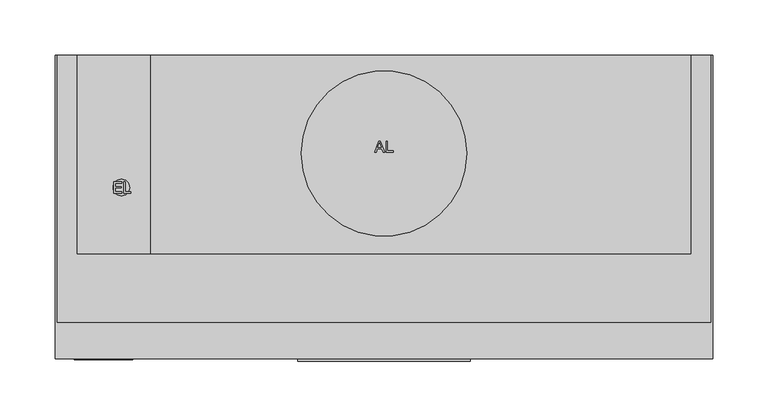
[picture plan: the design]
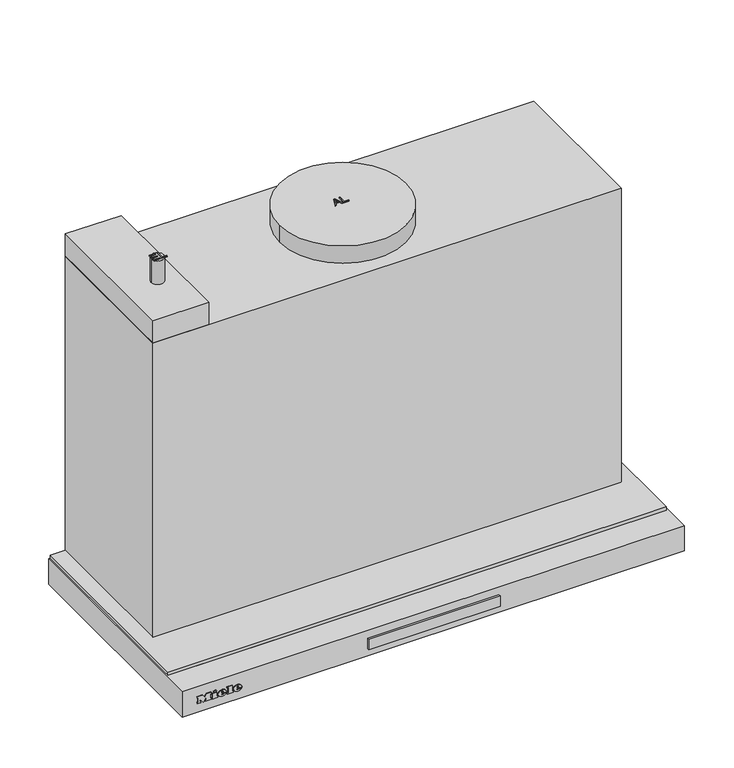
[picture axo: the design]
"""IFC4 building model written with IfcOpenShell, lengths in millimetres: proxy geometry."""

import ifcopenshell
import ifcopenshell.guid

model = None  # the IFC model being written
_history = None  # IfcOwnerHistory: only IFC2X3 demands one
_inside = {}  # id of a spatial element -> (the spatial element, [elements in it])
_under = {}  # id of a project, library or spatial element -> (it, [spatial elements below it])
_declared = {}  # id of a project -> (the project, [libraries it declares])
_typed = {}  # id of a type object -> (the type object, [elements of that type])
_made_of = {}  # id of a material, layer set ... -> (it, [elements and type objects made of it])


def new_model(schema):
    """Start an empty IFC model of exactly this schema.

    Asked for "IFC4X3", IfcOpenShell would pick the latest addendum, in which some entities
    have other attributes; the version numbers below select the first issue.
    IFC2X3 requires an IfcOwnerHistory on every rooted entity: one is made here for all.
    """
    global model, _history
    if schema == "IFC4X3":
        model = ifcopenshell.file(schema_version=(4, 3, 0, 0))
    else:
        model = ifcopenshell.file(schema=schema)
    _inside.clear()
    _under.clear()
    _declared.clear()
    _typed.clear()
    _made_of.clear()
    _history = None
    if model.schema == "IFC2X3":
        org = make("IfcOrganization", Name="unknown")
        user = make(
            "IfcPersonAndOrganization",
            ThePerson=make("IfcPerson", FamilyName="unknown"),
            TheOrganization=org,
        )
        app = make(
            "IfcApplication",
            ApplicationDeveloper=org,
            Version="unknown",
            ApplicationFullName="unknown",
            ApplicationIdentifier="unknown",
        )
        _history = make(
            "IfcOwnerHistory",
            OwningUser=user,
            OwningApplication=app,
            ChangeAction="ADDED",
            CreationDate=0,
        )
    return model


def make(cls, **values):
    """One entity of the class cls with the attributes given. An attribute that is None is left unset."""
    return model.create_entity(
        cls, **{name: value for name, value in values.items() if value is not None}
    )


def rooted(cls, **values):
    """An entity with a GlobalId (a new one), such as an element, a storey or a relation."""
    return make(cls, GlobalId=ifcopenshell.guid.new(), OwnerHistory=_history, **values)


def si_unit(unit_type, name, prefix=None):
    """IfcSIUnit, for example si_unit("LENGTHUNIT", "METRE", prefix="MILLI")."""
    return make("IfcSIUnit", UnitType=unit_type, Prefix=prefix, Name=name)


def assignment(units):
    """IfcUnitAssignment: the units of a project."""
    return None if units is None else make("IfcUnitAssignment", Units=units)


def point(xyz):
    """IfcCartesianPoint."""
    return None if xyz is None else make("IfcCartesianPoint", Coordinates=xyz)


def direction(xyz):
    """IfcDirection."""
    return None if xyz is None else make("IfcDirection", DirectionRatios=xyz)


def frame(location, z_axis=None, x_axis=None):
    """IfcAxis2Placement3D, a coordinate frame: its origin and axes. An axis left out is left unset."""
    return make(
        "IfcAxis2Placement3D",
        Location=point(location),
        Axis=direction(z_axis),
        RefDirection=direction(x_axis),
    )


def frame_2d(location, x_axis=None):
    """IfcAxis2Placement2D, a coordinate frame in the plane: its origin and x axis."""
    return make(
        "IfcAxis2Placement2D", Location=point(location), RefDirection=direction(x_axis)
    )


def origin():
    """The frame at (0, 0, 0) with its axes left unset."""
    return frame((0.0, 0.0, 0.0))


def origin_with_axes():
    """The frame at (0, 0, 0) with the z axis (0, 0, 1) and the x axis (1, 0, 0) written out."""
    return frame((0.0, 0.0, 0.0), z_axis=(0.0, 0.0, 1.0), x_axis=(1.0, 0.0, 0.0))


def place(relative_to, where):
    """IfcLocalPlacement: puts the frame where relative to a parent placement (None: the world)."""
    return make(
        "IfcLocalPlacement", PlacementRelTo=relative_to, RelativePlacement=where
    )


def context(
    kind, dimensions, precision=None, world=None, true_north=None, identifier=None
):
    """IfcGeometricRepresentationContext, for example the 3D "Model" context."""
    return make(
        "IfcGeometricRepresentationContext",
        ContextIdentifier=identifier,
        ContextType=kind,
        CoordinateSpaceDimension=dimensions,
        Precision=precision,
        WorldCoordinateSystem=world,
        TrueNorth=true_north,
    )


def project(units=None, contexts=None):
    """IfcProject with its units and contexts."""
    return rooted(
        "IfcProject",
        Name="project",
        RepresentationContexts=contexts,
        UnitsInContext=assignment(units),
    )


def spatial(cls, under=None, at=None, **own):
    """A site, building, storey or space (cls), placed at a placement, below another one or the project."""
    s = rooted(cls, ObjectPlacement=at, **own)
    if under is not None:
        _under.setdefault(under.id(), (under, []))[1].append(s)
    return s


def polyline(points):
    """IfcPolyline through the points."""
    return make("IfcPolyline", Points=[point(p) for p in points])


def circle_curve(where, radius):
    """IfcCircle in the frame where."""
    return make("IfcCircle", Position=where, Radius=radius)


def ellipse_curve(where, semi_axis1, semi_axis2):
    """IfcEllipse in the frame where."""
    return make(
        "IfcEllipse", Position=where, SemiAxis1=semi_axis1, SemiAxis2=semi_axis2
    )


def trimmed(basis, trim1, trim2, sense, master):
    """IfcTrimmedCurve: the piece of a basis curve between two trims."""
    return make(
        "IfcTrimmedCurve",
        BasisCurve=basis,
        Trim1=trim1,
        Trim2=trim2,
        SenseAgreement=sense,
        MasterRepresentation=master,
    )


def segment(curve, same_sense, transition):
    """IfcCompositeCurveSegment."""
    return make(
        "IfcCompositeCurveSegment",
        Transition=transition,
        SameSense=same_sense,
        ParentCurve=curve,
    )


def composite_curve(segments, self_intersect=None):
    """IfcCompositeCurve: segments joined end to end."""
    return make("IfcCompositeCurve", Segments=segments, SelfIntersect=self_intersect)


def outline(outer, holes=None, kind="AREA"):
    """IfcArbitraryClosedProfileDef: a profile drawn as a closed curve; with holes, ...WithVoids."""
    if holes is None:
        return make("IfcArbitraryClosedProfileDef", ProfileType=kind, OuterCurve=outer)
    return make(
        "IfcArbitraryProfileDefWithVoids",
        ProfileType=kind,
        OuterCurve=outer,
        InnerCurves=holes,
    )


def extrude(swept, where, along, depth):
    """IfcExtrudedAreaSolid: the profile swept, set in the frame where, extruded along a direction by depth."""
    return make(
        "IfcExtrudedAreaSolid",
        SweptArea=swept,
        Position=where,
        ExtrudedDirection=direction(along),
        Depth=depth,
    )


def faces_of(points, faces, orient=None, outer=None):
    """IfcFace entities. A face is a list of loops; a loop is a list of indices into points, from 0.

    orient and outer hold one flag for each loop. By default every Orientation is true, the
    first loop of a face is its IfcFaceOuterBound and the others are IfcFaceBound.
    """
    made = []
    for i, loops in enumerate(faces):
        bounds = []
        for j, loop in enumerate(loops):
            is_outer = j == 0 if outer is None else outer[i][j]
            bounds.append(
                make(
                    "IfcFaceOuterBound" if is_outer else "IfcFaceBound",
                    Bound=make("IfcPolyLoop", Polygon=[points[k] for k in loop]),
                    Orientation=True if orient is None else orient[i][j],
                )
            )
        made.append(make("IfcFace", Bounds=bounds))
    return made


def faceted_brep(points, faces, orient=None, outer=None, voids=None):
    """IfcFacetedBrep: a solid bounded by flat faces; with voids (closed shells), ...WithVoids."""
    shared = [point(p) for p in points]
    hull = make("IfcClosedShell", CfsFaces=faces_of(shared, faces, orient, outer))
    if voids is None:
        return make("IfcFacetedBrep", Outer=hull)
    return make(
        "IfcFacetedBrepWithVoids",
        Outer=hull,
        Voids=[
            make(cls, CfsFaces=faces_of(shared, fs, o, b)) for cls, fs, o, b in voids
        ],
    )


def shape(context_of_items, identifier, shape_type, items):
    """IfcShapeRepresentation: the items that make up one representation, for example the "Body"."""
    return make(
        "IfcShapeRepresentation",
        ContextOfItems=context_of_items,
        RepresentationIdentifier=identifier,
        RepresentationType=shape_type,
        Items=items,
    )


def source(mapping_origin, context_of_items, identifier, shape_type, items):
    """IfcRepresentationMap: a shape defined once, which mapped items show again and again."""
    return make(
        "IfcRepresentationMap",
        MappingOrigin=mapping_origin,
        MappedRepresentation=shape(context_of_items, identifier, shape_type, items),
    )


def transform(
    local_origin,
    x_axis=None,
    y_axis=None,
    z_axis=None,
    scale=None,
    scale2=None,
    scale3=None,
    uniform=True,
):
    """IfcCartesianTransformationOperator3D, or its non-uniform kind. x_axis, y_axis, z_axis: its Axis1, 2, 3."""
    if uniform:
        return make(
            "IfcCartesianTransformationOperator3D",
            Axis1=direction(x_axis),
            Axis2=direction(y_axis),
            LocalOrigin=point(local_origin),
            Scale=scale,
            Axis3=direction(z_axis),
        )
    return make(
        "IfcCartesianTransformationOperator3DnonUniform",
        Axis1=direction(x_axis),
        Axis2=direction(y_axis),
        LocalOrigin=point(local_origin),
        Scale=scale,
        Axis3=direction(z_axis),
        Scale2=scale2,
        Scale3=scale3,
    )


def mapped(mapping_source, mapping_target):
    """IfcMappedItem: shows the shape of a source again, moved by a transform."""
    return make(
        "IfcMappedItem", MappingSource=mapping_source, MappingTarget=mapping_target
    )


def made_of(thing, what):
    """Note that an element or type object is made of a material, layer set ...; save() writes the relation."""
    if what is not None:
        _made_of.setdefault(what.id(), (what, []))[1].append(thing)
    return thing


def element(
    cls,
    number,
    at=None,
    inside=None,
    cuts=None,
    type_object=None,
    material=None,
    context=None,
    identifier="Body",
    shape_type=None,
    held_by="IfcProductDefinitionShape",
    body=None,
    shapes=None,
    **own,
):
    """One element of the class cls, such as IfcWall. Its Tag is "e" and its number.

    at: its placement. inside: the storey or other place that contains it. cuts: it is an
    opening in that element (IfcRelVoidsElement). A single representation is given by context,
    identifier, shape_type and body (its items); several are given by shapes. held_by: the class
    of the entity that holds the representations. save() writes the other relations.
    """
    e = rooted(cls, Tag="e%d" % number, ObjectPlacement=at, **own)
    if body is not None:
        shapes = [shape(context, identifier, shape_type, body)]
    if shapes is not None:
        e.Representation = make(held_by, Representations=shapes)
    if inside is not None:
        _inside.setdefault(inside.id(), (inside, []))[1].append(e)
    if cuts is not None:
        rooted(
            "IfcRelVoidsElement", RelatingBuildingElement=cuts, RelatedOpeningElement=e
        )
    if type_object is not None:
        _typed.setdefault(type_object.id(), (type_object, []))[1].append(e)
    return made_of(e, material)


def aggregate(whole, parts):
    """IfcRelAggregates: a whole, such as a stair, and the parts it consists of."""
    return rooted("IfcRelAggregates", RelatingObject=whole, RelatedObjects=parts)


def save(model, path):
    """Write the relations noted so far, then the file.

    IfcRelAggregates (storeys below a building ...), IfcRelContainedInSpatialStructure (elements
    in a storey), IfcRelDefinesByType, IfcRelAssociatesMaterial and IfcRelDeclares: one each for
    every whole, place, type object, material and project.
    """
    for whole, parts in _under.values():
        aggregate(whole, parts)
    for where, things in _inside.values():
        rooted(
            "IfcRelContainedInSpatialStructure",
            RelatedElements=things,
            RelatingStructure=where,
        )
    for kind, things in _typed.values():
        rooted("IfcRelDefinesByType", RelatedObjects=things, RelatingType=kind)
    for what, things in _made_of.values():
        rooted("IfcRelAssociatesMaterial", RelatedObjects=things, RelatingMaterial=what)
    for by, libraries in _declared.values():
        rooted("IfcRelDeclares", RelatingContext=by, RelatedDefinitions=libraries)
    model.write(path)


def plane_surface(at):
    """IfcPlane: the flat surface through the origin of the frame at, square to its z axis."""
    return make("IfcPlane", Position=at)


def cylinder_surface(at, radius):
    """IfcCylindricalSurface: all points at the distance radius from the z axis of the frame at."""
    return make("IfcCylindricalSurface", Position=at, Radius=radius)


def revolved_surface(curve, axis_point, axis_direction):
    """IfcSurfaceOfRevolution: the curve turned about the line through axis_point along axis_direction."""
    return make(
        "IfcSurfaceOfRevolution",
        SweptCurve=make("IfcArbitraryOpenProfileDef", ProfileType="CURVE", Curve=curve),
        AxisPosition=make("IfcAxis1Placement", Location=point(axis_point), Axis=direction(axis_direction)),
    )


def extruded_surface(curve, direction_of_extrusion, depth):
    """IfcSurfaceOfLinearExtrusion: the curve pushed along a direction by depth."""
    return make(
        "IfcSurfaceOfLinearExtrusion",
        SweptCurve=make("IfcArbitraryOpenProfileDef", ProfileType="CURVE", Curve=curve),
        ExtrudedDirection=direction(direction_of_extrusion),
        Depth=depth,
    )


def advanced_brep(points, edges, surfaces, faces):
    """IfcAdvancedBrep: a solid bounded by faces that lie on surfaces and meet in shared edges.

    An edge is (start, end): straight between two places in points (the first is 0);
    or (start, end, curve); or (start, end, curve, False) where it runs against its curve.
    A face is (place in surfaces, loops), or (place, loops, False) where it looks against
    its surface's normal. A loop lists edges by number (the first is 1), with a minus sign
    where the edge is run from its end to its start. The first loop is the outer one.
    """
    corners = [point(p) for p in points]
    vertices = [make("IfcVertexPoint", VertexGeometry=c) for c in corners]
    made = []
    for start, end, *more in edges:
        made.append(
            make(
                "IfcEdgeCurve",
                EdgeStart=vertices[start],
                EdgeEnd=vertices[end],
                EdgeGeometry=more[0] if more else make("IfcPolyline", Points=[corners[start], corners[end]]),
                SameSense=more[1] if len(more) > 1 else True,
            )
        )
    hull = []
    for where, loops, *sense in faces:
        bounds = []
        for j, loop in enumerate(loops):
            ring = [make("IfcOrientedEdge", EdgeElement=made[abs(k) - 1], Orientation=k > 0) for k in loop]
            bounds.append(
                make(
                    "IfcFaceOuterBound" if j == 0 else "IfcFaceBound",
                    Bound=make("IfcEdgeLoop", EdgeList=ring),
                    Orientation=True,
                )
            )
        hull.append(make("IfcAdvancedFace", Bounds=bounds, FaceSurface=surfaces[where], SameSense=sense[0] if sense else True))
    return make("IfcAdvancedBrep", Outer=make("IfcClosedShell", CfsFaces=hull))


def specialty_equipment_90b96d87(model_context):
    return source(origin(), model_context, "Body", "SolidModel", [
        extrude(outline(polyline([(78.0, -275.0), (78.0, -277.3978707), (-78.0, -277.3978707), (-78.0, -275.0), (78.0, -275.0)])), frame((0.0, 0.0, -23.0389651), z_axis=(0.0, 0.0, 1.0), x_axis=(1.0, 0.0, 0.0)), (0.0, 0.0, 1.0), 13.3389155),
        advanced_brep(
        [(-233.4590019, -276.0, -18.7681017), (-233.4590019, -276.0, -17.8894017), (-227.6387019, -276.0, -17.8894017), (-237.7655019, -276.0, -17.8894017), (-235.3730019, -276.0, -20.8300017), (-227.7866019, -276.0, -18.7681017), (-230.4140019, -276.0, -18.7681017), (-232.4846019, -276.0, -19.7425017), (-233.4590019, -276.0, -16.7758017), (-233.4590019, -276.0, -15.8275017), (-231.9713019, -276.0, -15.8275017), (-231.9713019, -276.0, -16.7758017), (-233.4590019, -275.0, -18.7681017), (-232.4846019, -275.0, -19.7425017), (-230.4140019, -275.0, -18.7681017), (-227.7866019, -275.0, -18.7681017), (-235.3730019, -275.0, -20.8300017), (-237.7655019, -275.0, -17.8894017), (-227.6387019, -275.0, -17.8894017), (-233.4590019, -275.0, -17.8894017), (-233.4590019, -275.0, -16.7758017), (-231.9713019, -275.0, -16.7758017), (-231.9713019, -275.0, -15.8275017), (-233.4590019, -275.0, -15.8275017)],
        [
            (0, 1),
            (1, 2),
            (2, 3, ellipse_curve(frame((-232.7021019, -276.0, -17.8894017), z_axis=(0.0, -1.0, 0.0), x_axis=(-1.0, 0.0, 0.0)), 5.0634, 4.1847)),
            (3, 4, circle_curve(frame((-234.3985544, -276.0, -17.5936017), z_axis=(0.0, -1.0, 0.0), x_axis=(0.0, 0.0, -1.0)), 3.3799161)),
            (4, 5, circle_curve(frame((-232.8034638, -276.0, -15.2968017), z_axis=(0.0, -1.0, 0.0), x_axis=(0.0, 0.0, -1.0)), 6.1007236)),
            (5, 6),
            (6, 7, circle_curve(frame((-232.0593254, -276.0, -17.9590017), z_axis=(0.0, 1.0, 0.0), x_axis=(0.0, 0.0, -1.0)), 1.8335027)),
            (7, 0, circle_curve(frame((-232.4846019, -276.0, -18.7681017), z_axis=(0.0, 1.0, 0.0), x_axis=(0.0, 0.0, -1.0)), 0.9744)),
            (8, 9),
            (9, 10, circle_curve(frame((-232.7151519, -276.0, -15.8275017), z_axis=(0.0, 1.0, 0.0), x_axis=(0.0, 0.0, -1.0)), 0.74385)),
            (10, 11),
            (11, 8),
            (12, 13, circle_curve(frame((-232.4846019, -275.0, -18.7681017), z_axis=(0.0, -1.0, 0.0), x_axis=(0.0, 0.0, -1.0)), 0.9744)),
            (13, 14, circle_curve(frame((-232.0593254, -275.0, -17.9590017), z_axis=(0.0, -1.0, 0.0), x_axis=(0.0, 0.0, -1.0)), 1.8335027)),
            (14, 15),
            (15, 16, circle_curve(frame((-232.8034638, -275.0, -15.2968017), z_axis=(0.0, 1.0, 0.0), x_axis=(0.0, 0.0, -1.0)), 6.1007236)),
            (16, 17, circle_curve(frame((-234.3985544, -275.0, -17.5936017), z_axis=(0.0, 1.0, 0.0), x_axis=(0.0, 0.0, -1.0)), 3.3799161)),
            (17, 18, ellipse_curve(frame((-232.7021019, -275.0, -17.8894017), z_axis=(0.0, 1.0, 0.0), x_axis=(-1.0, 0.0, 0.0)), 5.0634, 4.1847)),
            (18, 19),
            (19, 12),
            (20, 21),
            (21, 22),
            (22, 23, circle_curve(frame((-232.7151519, -275.0, -15.8275017), z_axis=(0.0, -1.0, 0.0), x_axis=(0.0, 0.0, -1.0)), 0.74385)),
            (23, 20),
            (0, 12),
            (19, 1),
            (18, 2),
            (5, 15),
            (14, 6),
            (17, 3),
            (13, 7),
            (16, 4),
            (8, 20),
            (23, 9),
            (22, 10),
            (21, 11),
        ],
        [
            plane_surface(frame((-233.4590019, -276.0, -17.8894017), z_axis=(0.0, -1.0, 0.0), x_axis=(0.0, 0.0, 1.0))),
            plane_surface(frame((-233.4590019, -275.0, -17.8894017), z_axis=(0.0, 1.0, 0.0), x_axis=(0.0, 0.0, -1.0))),
            plane_surface(frame((-233.4590019, -276.0, -18.7681017), z_axis=(1.0, 0.0, 0.0), x_axis=(0.0, 1.0, 0.0))),
            plane_surface(frame((-233.4590019, -276.0, -17.8894017), z_axis=(0.0, 0.0, -1.0), x_axis=(0.0, 1.0, 0.0))),
            plane_surface(frame((-227.7866019, -276.0, -18.7681017), z_axis=(0.0, 0.0, 1.0), x_axis=(0.0, 1.0, 0.0))),
            extruded_surface(trimmed(ellipse_curve(frame((-232.7021019, -274.0, -17.8894017), z_axis=(0.0, -1.0, 0.0), x_axis=(-1.0, 0.0, 0.0)), 5.0634, 4.1847), [point((-227.6387019, -274.0, -17.8894017))], [point((-237.7655019, -274.0, -17.8894017))], True, "CARTESIAN"), (0.0, -1.0, 0.0), 1.0),
            revolved_surface(polyline([(-232.0593254, -275.0, -19.792504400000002), (-232.0593254, -276.0, -19.792504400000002)]), (-232.0593254, -275.0, -17.9590017), (0.0, 1.0, 0.0)),
            revolved_surface(polyline([(-232.4846019, -275.0, -19.7425017), (-232.4846019, -276.0, -19.7425017)]), (-232.4846019, -275.0, -18.7681017), (0.0, 1.0, 0.0)),
            cylinder_surface(frame((-234.3985544, -275.0, -17.5936017), z_axis=(0.0, -1.0, 0.0), x_axis=(0.0, 0.0, -1.0)), 3.3799161),
            cylinder_surface(frame((-232.8034638, -275.0, -15.2968017), z_axis=(0.0, -1.0, 0.0), x_axis=(0.0, 0.0, -1.0)), 6.1007236),
            plane_surface(frame((-233.4590019, -276.0, -16.7758017), z_axis=(1.0, 0.0, 0.0), x_axis=(0.0, 1.0, 0.0))),
            revolved_surface(polyline([(-232.7151519, -275.0, -16.571351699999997), (-232.7151519, -276.0, -16.571351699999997)]), (-232.7151519, -275.0, -15.8275017), (0.0, 1.0, 0.0)),
            plane_surface(frame((-231.9713019, -276.0, -15.8275017), z_axis=(-1.0, 0.0, 0.0), x_axis=(0.0, 1.0, 0.0))),
            plane_surface(frame((-231.9713019, -276.0, -16.7758017), z_axis=(0.0, 0.0, 1.0), x_axis=(0.0, 1.0, 0.0))),
        ],
        [
            (0, [[1, 2, 3, 4, 5, 6, 7, 8], [9, 10, 11, 12]]),
            (1, [[13, 14, 15, 16, 17, 18, 19, 20], [21, 22, 23, 24]]),
            (2, [[-1, 25, -20, 26]]),
            (3, [[-2, -26, -19, 27]]),
            (4, [[-6, 28, -15, 29]]),
            (5, [[-3, -27, -18, 30]]),
            (6, [[-7, -29, -14, 31]]),
            (7, [[-8, -31, -13, -25]]),
            (8, [[-4, -30, -17, 32]]),
            (9, [[-5, -32, -16, -28]]),
            (10, [[-9, 33, -24, 34]]),
            (11, [[-10, -34, -23, 35]]),
            (12, [[-11, -35, -22, 36]]),
            (13, [[-12, -36, -21, -33]]),
        ],
    ),
        advanced_brep(
        [(-251.6159019, -276.0, -18.7681017), (-251.6159019, -276.0, -17.8894017), (-245.7956019, -276.0, -17.8894017), (-255.9224019, -276.0, -17.8894017), (-253.5299019, -276.0, -20.8300017), (-245.9435019, -276.0, -18.7681017), (-248.5709019, -276.0, -18.7681017), (-250.6415019, -276.0, -19.7425017), (-251.6159019, -276.0, -16.7758017), (-251.6159019, -276.0, -15.8275017), (-250.1282019, -276.0, -15.8275017), (-250.1282019, -276.0, -16.7758017), (-251.6159019, -275.0, -18.7681017), (-250.6415019, -275.0, -19.7425017), (-248.5709019, -275.0, -18.7681017), (-245.9435019, -275.0, -18.7681017), (-253.5299019, -275.0, -20.8300017), (-255.9224019, -275.0, -17.8894017), (-245.7956019, -275.0, -17.8894017), (-251.6159019, -275.0, -17.8894017), (-251.6159019, -275.0, -16.7758017), (-250.1282019, -275.0, -16.7758017), (-250.1282019, -275.0, -15.8275017), (-251.6159019, -275.0, -15.8275017)],
        [
            (0, 1),
            (1, 2),
            (2, 3, ellipse_curve(frame((-250.8590019, -276.0, -17.8894017), z_axis=(0.0, -1.0, 0.0), x_axis=(-1.0, 0.0, 0.0)), 5.0634, 4.1847)),
            (3, 4, circle_curve(frame((-252.5554544, -276.0, -17.5936017), z_axis=(0.0, -1.0, 0.0), x_axis=(0.0, 0.0, -1.0)), 3.3799161)),
            (4, 5, circle_curve(frame((-250.9603638, -276.0, -15.2968017), z_axis=(0.0, -1.0, 0.0), x_axis=(0.0, 0.0, -1.0)), 6.1007236)),
            (5, 6),
            (6, 7, circle_curve(frame((-250.2162254, -276.0, -17.9590017), z_axis=(0.0, 1.0, 0.0), x_axis=(0.0, 0.0, -1.0)), 1.8335027)),
            (7, 0, circle_curve(frame((-250.6415019, -276.0, -18.7681017), z_axis=(0.0, 1.0, 0.0), x_axis=(0.0, 0.0, -1.0)), 0.9744)),
            (8, 9),
            (9, 10, circle_curve(frame((-250.8720519, -276.0, -15.8275017), z_axis=(0.0, 1.0, 0.0), x_axis=(0.0, 0.0, -1.0)), 0.74385)),
            (10, 11),
            (11, 8),
            (12, 13, circle_curve(frame((-250.6415019, -275.0, -18.7681017), z_axis=(0.0, -1.0, 0.0), x_axis=(0.0, 0.0, -1.0)), 0.9744)),
            (13, 14, circle_curve(frame((-250.2162254, -275.0, -17.9590017), z_axis=(0.0, -1.0, 0.0), x_axis=(0.0, 0.0, -1.0)), 1.8335027)),
            (14, 15),
            (15, 16, circle_curve(frame((-250.9603638, -275.0, -15.2968017), z_axis=(0.0, 1.0, 0.0), x_axis=(0.0, 0.0, -1.0)), 6.1007236)),
            (16, 17, circle_curve(frame((-252.5554544, -275.0, -17.5936017), z_axis=(0.0, 1.0, 0.0), x_axis=(0.0, 0.0, -1.0)), 3.3799161)),
            (17, 18, ellipse_curve(frame((-250.8590019, -275.0, -17.8894017), z_axis=(0.0, 1.0, 0.0), x_axis=(-1.0, 0.0, 0.0)), 5.0634, 4.1847)),
            (18, 19),
            (19, 12),
            (20, 21),
            (21, 22),
            (22, 23, circle_curve(frame((-250.8720519, -275.0, -15.8275017), z_axis=(0.0, -1.0, 0.0), x_axis=(0.0, 0.0, -1.0)), 0.74385)),
            (23, 20),
            (0, 12),
            (19, 1),
            (18, 2),
            (5, 15),
            (14, 6),
            (17, 3),
            (13, 7),
            (16, 4),
            (8, 20),
            (23, 9),
            (22, 10),
            (21, 11),
        ],
        [
            plane_surface(frame((-251.6159019, -276.0, -17.8894017), z_axis=(0.0, -1.0, 0.0), x_axis=(0.0, 0.0, 1.0))),
            plane_surface(frame((-251.6159019, -275.0, -17.8894017), z_axis=(0.0, 1.0, 0.0), x_axis=(0.0, 0.0, -1.0))),
            plane_surface(frame((-251.6159019, -276.0, -18.7681017), z_axis=(1.0, 0.0, 0.0), x_axis=(0.0, 1.0, 0.0))),
            plane_surface(frame((-251.6159019, -276.0, -17.8894017), z_axis=(0.0, 0.0, -1.0), x_axis=(0.0, 1.0, 0.0))),
            plane_surface(frame((-245.9435019, -276.0, -18.7681017), z_axis=(0.0, 0.0, 1.0), x_axis=(0.0, 1.0, 0.0))),
            extruded_surface(trimmed(ellipse_curve(frame((-250.8590019, -274.0, -17.8894017), z_axis=(0.0, -1.0, 0.0), x_axis=(-1.0, 0.0, 0.0)), 5.0634, 4.1847), [point((-245.7956019, -274.0, -17.8894017))], [point((-255.9224019, -274.0, -17.8894017))], True, "CARTESIAN"), (0.0, -1.0, 0.0), 1.0),
            revolved_surface(polyline([(-250.2162254, -275.0, -19.792504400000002), (-250.2162254, -276.0, -19.792504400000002)]), (-250.2162254, -275.0, -17.9590017), (0.0, 1.0, 0.0)),
            revolved_surface(polyline([(-250.6415019, -275.0, -19.7425017), (-250.6415019, -276.0, -19.7425017)]), (-250.6415019, -275.0, -18.7681017), (0.0, 1.0, 0.0)),
            cylinder_surface(frame((-252.5554544, -275.0, -17.5936017), z_axis=(0.0, -1.0, 0.0), x_axis=(0.0, 0.0, -1.0)), 3.3799161),
            cylinder_surface(frame((-250.9603638, -275.0, -15.2968017), z_axis=(0.0, -1.0, 0.0), x_axis=(0.0, 0.0, -1.0)), 6.1007236),
            plane_surface(frame((-251.6159019, -276.0, -16.7758017), z_axis=(1.0, 0.0, 0.0), x_axis=(0.0, 1.0, 0.0))),
            revolved_surface(polyline([(-250.8720519, -275.0, -16.571351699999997), (-250.8720519, -276.0, -16.571351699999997)]), (-250.8720519, -275.0, -15.8275017), (0.0, 1.0, 0.0)),
            plane_surface(frame((-250.1282019, -276.0, -15.8275017), z_axis=(-1.0, 0.0, 0.0), x_axis=(0.0, 1.0, 0.0))),
            plane_surface(frame((-250.1282019, -276.0, -16.7758017), z_axis=(0.0, 0.0, 1.0), x_axis=(0.0, 1.0, 0.0))),
        ],
        [
            (0, [[1, 2, 3, 4, 5, 6, 7, 8], [9, 10, 11, 12]]),
            (1, [[13, 14, 15, 16, 17, 18, 19, 20], [21, 22, 23, 24]]),
            (2, [[-1, 25, -20, 26]]),
            (3, [[-2, -26, -19, 27]]),
            (4, [[-6, 28, -15, 29]]),
            (5, [[-3, -27, -18, 30]]),
            (6, [[-7, -29, -14, 31]]),
            (7, [[-8, -31, -13, -25]]),
            (8, [[-4, -30, -17, 32]]),
            (9, [[-5, -32, -16, -28]]),
            (10, [[-9, 33, -24, 34]]),
            (11, [[-10, -34, -23, 35]]),
            (12, [[-11, -35, -22, 36]]),
            (13, [[-12, -36, -21, -33]]),
        ],
    ),
        extrude(outline(polyline([(-12.6433017, -261.1250019), (-14.0527017, -260.4638019), (-12.6781017, -257.5145019), (-11.2687017, -258.1670019), (-12.6433017, -261.1250019)])), frame((0.0, -276.0, 0.0), z_axis=(0.0, 1.0, 0.0), x_axis=(0.0, 0.0, 1.0)), (0.0, 0.0, 1.0), 1.0),
        extrude(outline(polyline([(-14.2441017, -263.2739019), (-15.8014017, -263.2739019), (-15.8014017, -262.2386019), (-19.3684017, -262.2386019), (-19.3684017, -263.2739019), (-20.8300017, -263.2739019), (-20.8300017, -256.4096019), (-19.3684017, -256.4096019), (-19.3684017, -257.4188019), (-14.2441017, -257.4188019), (-14.2441017, -263.2739019)])), frame((0.0, -276.0, 0.0), z_axis=(0.0, 1.0, 0.0), x_axis=(0.0, 0.0, 1.0)), (0.0, 0.0, 1.0), 1.0),
        extrude(outline(polyline([(-13.5481017, -245.3084019), (-13.5481017, -244.2644019), (-19.3684017, -244.2644019), (-19.3684017, -245.3084019), (-20.8300017, -245.3084019), (-20.8300017, -238.2527019), (-19.3684017, -238.2527019), (-19.3684017, -239.3228019), (-12.1300017, -239.3228019), (-12.1300017, -245.3084019), (-13.5481017, -245.3084019)])), frame((0.0, -276.0, 0.0), z_axis=(0.0, 1.0, 0.0), x_axis=(0.0, 0.0, 1.0)), (0.0, 0.0, 1.0), 1.0),
        extrude(outline(polyline([(-13.5481017, -280.6130019), (-13.5481017, -279.5603019), (-19.3684017, -279.5603019), (-19.3684017, -280.6130019), (-20.8300017, -280.6130019), (-20.8300017, -276.7850019), (-19.3684017, -276.7850019), (-19.3684017, -277.8290019), (-15.6719769, -277.8290019), (-20.8300017, -273.9401019), (-15.5772794, -270.0338019), (-19.3684017, -270.0338019), (-19.3684017, -271.1039019), (-20.8300017, -271.1039019), (-20.8300017, -264.1613019), (-19.3684017, -264.1613019), (-19.3684017, -265.2662019), (-13.5481017, -265.2662019), (-13.5481017, -264.1613019), (-12.1300017, -264.1613019), (-12.1300017, -269.4596019), (-15.3925017, -272.0000019), (-12.1300017, -274.5491019), (-12.1300017, -280.6130019), (-13.5481017, -280.6130019)])), frame((0.0, -276.0, 0.0), z_axis=(0.0, 1.0, 0.0), x_axis=(0.0, 0.0, 1.0)), (0.0, 0.0, 1.0), 1.0),
        extrude(outline(polyline([(278.0, -180.0), (-278.0, -180.0), (-278.0, 0.0), (278.0, 0.0), (278.0, -180.0)])), frame((0.0, 0.0, 4.0), z_axis=(0.0, 0.0, 1.0), x_axis=(1.0, 0.0, 0.0)), (0.0, 0.0, 1.0), 369.0),
        extrude(outline(composite_curve([segment(trimmed(circle_curve(frame_2d((0.0, -89.0)), 75.0), [point((-75.0, -89.0))], [point((75.0, -89.0))], False, "CARTESIAN"), True, "CONTINUOUS"), segment(trimmed(circle_curve(frame_2d((0.0, -89.0)), 75.0), [point((75.0, -89.0))], [point((-75.0, -89.0))], False, "CARTESIAN"), True, "CONTINUOUS")], self_intersect=False)), frame((0.0, 0.0, 373.0), z_axis=(0.0, 0.0, 1.0), x_axis=(1.0, 0.0, 0.0)), (0.0, 0.0, 1.0), 22.0),
        extrude(outline(polyline([(-278.0, -180.0), (-278.0, 0.0), (-212.0, 0.0), (-212.0, -180.0), (-278.0, -180.0)])), frame((0.0, 0.0, 373.0), z_axis=(0.0, 0.0, 1.0), x_axis=(1.0, 0.0, 0.0)), (0.0, 0.0, 1.0), 28.0),
        extrude(outline(polyline([(-8.547125, -87.975609), (-4.5372113, -77.929978), (-3.4679009, -77.929978), (0.5420128, -87.975609), (-0.7848149, -87.975609), (-1.9350593, -84.8363493), (-6.0725055, -84.8363493), (-7.2202973, -87.975609), (-8.547125, -87.975609)]), holes=[polyline([(-5.6114267, -83.5806455), (-2.3936855, -83.5806455), (-3.2986752, -81.110931), (-4.0025561, -79.1856819), (-4.6279555, -80.8951069), (-5.6114267, -83.5806455)])]), frame((0.0, 0.0, 395.0), z_axis=(0.0, 0.0, 1.0), x_axis=(1.0, 0.0, 0.0)), (0.0, 0.0, 1.0), 1.0),
        extrude(outline(polyline([(1.8835558, -87.975609), (1.8835558, -77.929978), (3.1392597, -77.929978), (3.1392597, -86.7199052), (8.1620752, -86.7199052), (8.1620752, -87.975609), (1.8835558, -87.975609)])), frame((0.0, 0.0, 395.0), z_axis=(0.0, 0.0, 1.0), x_axis=(1.0, 0.0, 0.0)), (0.0, 0.0, 1.0), 1.0),
        extrude(outline(polyline([(296.0, 0.0), (296.0, -242.0), (-296.0, -242.0), (-296.0, 0.0), (296.0, 0.0)])), origin_with_axes(), (0.0, 0.0, 1.0), 4.0),
        extrude(outline(polyline([(120.0, -19.25), (120.0, -31.75), (-120.0, -31.75), (-120.0, -19.25), (120.0, -19.25)])), frame((0.0, 0.0, -23.0), z_axis=(0.0, 0.0, 1.0), x_axis=(1.0, 0.0, 0.0)), (0.0, 0.0, 1.0), 1.785426),
        extrude(outline(polyline([(181.0813184, -268.0), (181.0813184, -246.0), (249.0, -246.0), (249.0, -268.0), (181.0813184, -268.0)])), frame((0.0, 0.0, -33.3019181), z_axis=(0.0, 0.0, 1.0), x_axis=(1.0, 0.0, 0.0)), (0.0, 0.0, 1.0), 1.3019181),
        extrude(outline(polyline([(-249.0, -268.0), (-249.0, -246.0), (-181.0, -246.0), (-181.0, -268.0), (-249.0, -268.0)])), frame((0.0, 0.0, -33.3019181), z_axis=(0.0, 0.0, 1.0), x_axis=(1.0, 0.0, 0.0)), (0.0, 0.0, 1.0), 1.3019181),
        extrude(outline(composite_curve([segment(trimmed(circle_curve(frame_2d((-238.0, -120.0)), 7.5), [point((-230.5, -120.0))], [point((-245.5, -120.0))], False, "CARTESIAN"), True, "CONTINUOUS"), segment(trimmed(circle_curve(frame_2d((-238.0, -120.0)), 7.5), [point((-245.5, -120.0))], [point((-230.5, -120.0))], False, "CARTESIAN"), True, "CONTINUOUS")], self_intersect=False)), frame((0.0, 0.0, 401.0), z_axis=(0.0, 0.0, 1.0), x_axis=(1.0, 0.0, 0.0)), (0.0, 0.0, 1.0), 30.0),
        extrude(outline(polyline([(-235.640443, -124.9184735), (-235.640443, -114.8728425), (-234.3847391, -114.8728425), (-234.3847391, -123.6627696), (-229.3619236, -123.6627696), (-229.3619236, -124.9184735), (-235.640443, -124.9184735)])), frame((0.0, 0.0, 431.0), z_axis=(0.0, 0.0, 1.0), x_axis=(1.0, 0.0, 0.0)), (0.0, 0.0, 1.0), 1.0),
        extrude(outline(polyline([(-244.9012591, -124.9184735), (-244.9012591, -114.8728425), (-237.6809618, -114.8728425), (-237.6809618, -116.1285464), (-243.6455552, -116.1285464), (-243.6455552, -119.1108431), (-237.9948878, -119.1108431), (-237.9948878, -120.366547), (-243.6455552, -120.366547), (-243.6455552, -123.6627696), (-237.5239988, -123.6627696), (-237.5239988, -124.9184735), (-244.9012591, -124.9184735)])), frame((0.0, 0.0, 431.0), z_axis=(0.0, 0.0, 1.0), x_axis=(1.0, 0.0, 0.0)), (0.0, 0.0, 1.0), 1.0),
        extrude(outline(polyline([(-298.0, 0.0), (-263.0, 0.0), (-263.0, -242.0), (263.0, -242.0), (263.0, 0.0), (298.0, 0.0), (298.0, -275.0), (-298.0, -275.0), (-298.0, 0.0)])), frame((0.0, 0.0, -32.0), z_axis=(0.0, 0.0, 1.0), x_axis=(1.0, 0.0, 0.0)), (0.0, 0.0, 1.0), 32.0),
        faceted_brep([(-126.0, -39.0, -24.0), (-126.0, -39.0, 0.0), (126.0, -39.0, 0.0), (126.0, -39.0, -24.0), (-126.0, -12.0, -24.0), (-126.0, -12.0, 0.0), (126.0, -12.0, -24.0), (126.0, -12.0, 0.0), (-263.0, -242.0, 0.0), (-263.0, 0.0, 0.0), (-263.0, 0.0, -24.0), (-263.0, -52.0, -24.0), (-263.0, -52.0, -25.0), (-263.0, -242.0, -25.0), (263.0, -52.0, -25.0), (263.0, -242.0, -25.0), (263.0, -52.0, -24.0), (263.0, 0.0, -24.0), (263.0, 0.0, 0.0), (263.0, -242.0, 0.0)], [[[0, 1, 2, 3]], [[4, 5, 1, 0]], [[6, 7, 5, 4]], [[8, 9, 10, 11, 12, 13]], [[13, 12, 14, 15]], [[16, 11, 10, 17], [6, 4, 0, 3]], [[11, 16, 14, 12]], [[18, 9, 8, 19], [5, 7, 2, 1]], [[9, 18, 17, 10]], [[19, 8, 13, 15]], [[18, 19, 15, 14, 16, 17]], [[7, 6, 3, 2]]]),
        extrude(outline(polyline([(126.0, -12.0), (126.0, -39.0), (-126.0, -39.0), (-126.0, -12.0), (126.0, -12.0)]), holes=[polyline([(120.0, -19.25), (-120.0, -19.25), (-120.0, -31.75), (120.0, -31.75), (120.0, -19.25)])]), frame((0.0, 0.0, -21.214574), z_axis=(0.0, 0.0, 1.0), x_axis=(1.0, 0.0, 0.0)), (0.0, 0.0, 1.0), 21.214574),
    ])


if __name__ == "__main__":
    model = new_model("IFC4")
    model_context = context("Model", 3, world=origin())
    ifc_project = project(units=[si_unit("LENGTHUNIT", "METRE", prefix="MILLI")], contexts=[model_context])
    site = spatial("IfcSite", under=ifc_project)
    building = spatial("IfcBuilding", under=site)
    placement = place(None, origin())
    specialty_equipment_shape = specialty_equipment_90b96d87(model_context)
    element("IfcBuildingElementProxy", 1, Name="Specialty Equipment", at=placement, inside=building, context=model_context, shape_type="MappedRepresentation", body=[
        mapped(specialty_equipment_shape, transform((0.0, 0.0, 0.0), x_axis=(1.0, 0.0, 0.0), y_axis=(0.0, 1.0, 0.0), z_axis=(0.0, 0.0, 1.0))),
    ])
    save(model, "model.ifc")
